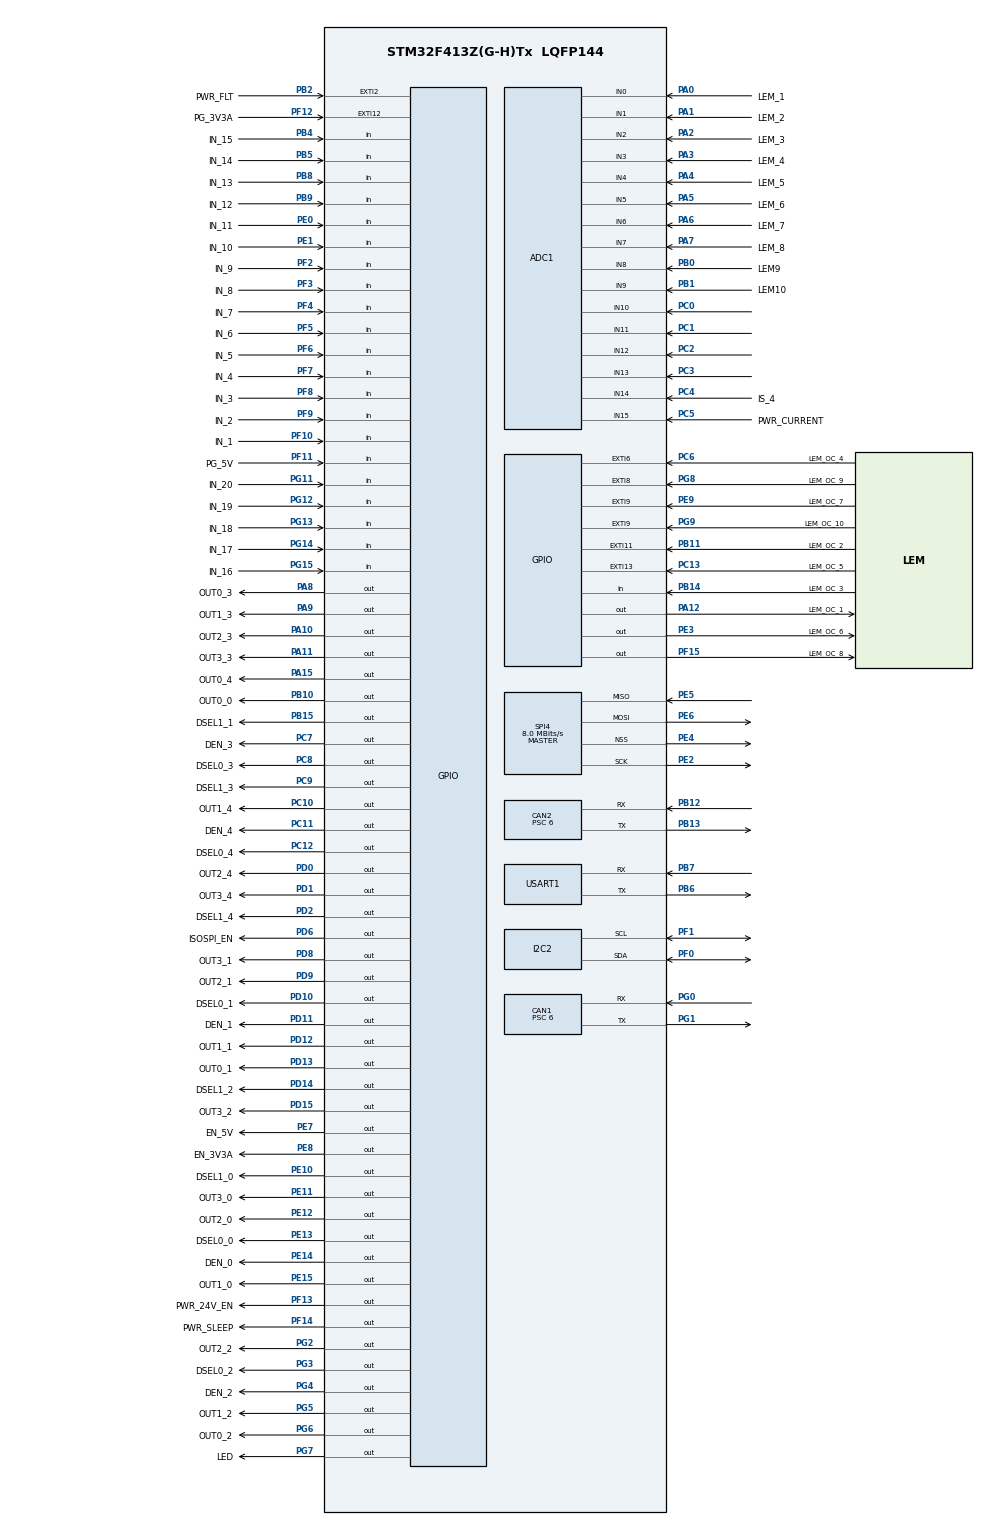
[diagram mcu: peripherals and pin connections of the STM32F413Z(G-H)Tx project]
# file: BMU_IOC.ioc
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ADC1.Channel-0\#ChannelRegularConversion=ADC_CHANNEL_0
ADC1.NbrOfConversionFlag=1
ADC1.Rank-0\#ChannelRegularConversion=1
ADC1.SamplingTime-0\#ChannelRegularConversion=ADC_SAMPLETIME_3CYCLES
ADC1.master=1
CAN1.BS1=CAN_BS1_13TQ
CAN1.BS2=CAN_BS2_2TQ
CAN1.CalculateBaudRate=500000
CAN1.CalculateTimeBit=2000
CAN1.CalculateTimeQuantum=125.0
CAN1.Prescaler=6
CAN2.BS1=CAN_BS1_13TQ
CAN2.BS2=CAN_BS2_2TQ
CAN2.CalculateBaudRate=500000
CAN2.CalculateTimeBit=2000
CAN2.CalculateTimeQuantum=125.0
CAN2.Prescaler=6
Mcu.Family=STM32F4
Mcu.Name=STM32F413Z(G-H)Tx
Mcu.Package=LQFP144
NVIC.PriorityGroup=NVIC_PRIORITYGROUP_4
PA0.GPIO_Label=LEM_1
PA0.Signal=ADCx_IN0
PA1.GPIO_Label=LEM_2
PA1.Signal=ADCx_IN1
PA10.GPIO_Label=OUT2_3
PA10.Signal=GPIO_Output
PA11.GPIO_Label=OUT3_3
PA11.Signal=GPIO_Output
PA12.GPIO_Label=LEM_OC_1
PA12.Signal=GPIO_Output
PA13.Mode=Trace_Asynchronous_SW
PA13.Signal=SYS_JTMS-SWDIO
PA14.Mode=Trace_Asynchronous_SW
PA14.Signal=SYS_JTCK-SWCLK
PA15.GPIO_Label=OUT0_4
PA15.Signal=GPIO_Output
PA2.GPIO_Label=LEM_3
PA2.Signal=ADCx_IN2
PA3.GPIO_Label=LEM_4
PA3.Signal=ADCx_IN3
PA4.GPIO_Label=LEM_5
PA4.Signal=ADCx_IN4
PA5.GPIO_Label=LEM_6
PA5.Signal=ADCx_IN5
PA6.GPIO_Label=LEM_7
PA6.Signal=ADCx_IN6
PA7.GPIO_Label=LEM_8
PA7.Signal=ADCx_IN7
PA8.GPIO_Label=OUT0_3
PA8.Signal=GPIO_Output
PA9.GPIO_Label=OUT1_3
PA9.Signal=GPIO_Output
PB0.GPIO_Label=LEM9
PB0.Signal=ADCx_IN8
PB1.GPIO_Label=LEM10
PB1.Signal=ADCx_IN9
PB10.GPIO_Label=OUT0_0
PB10.Signal=GPIO_Output
PB11.GPIO_Label=LEM_OC_2
PB11.Signal=GPXTI11
PB12.Mode=CAN_Activate
PB12.Signal=CAN2_RX
PB13.Mode=CAN_Activate
PB13.Signal=CAN2_TX
PB14.GPIO_Label=LEM_OC_3
PB14.Signal=GPIO_Input
PB15.GPIO_Label=DSEL1_1
PB15.Signal=GPIO_Output
PB2.GPIO_Label=PWR_FLT
PB2.Signal=GPXTI2
PB3.Mode=Trace_Asynchronous_SW
PB3.Signal=SYS_JTDO-SWO
PB4.GPIO_Label=IN_15
PB4.Signal=GPIO_Input
PB5.GPIO_Label=IN_14
PB5.Signal=GPIO_Input
PB6.Mode=Asynchronous
PB6.Signal=USART1_TX
PB7.Mode=Asynchronous
PB7.Signal=USART1_RX
PB8.GPIO_Label=IN_13
PB8.Signal=GPIO_Input
PB9.GPIO_Label=IN_12
PB9.Signal=GPIO_Input
PC0.Signal=ADCx_IN10
PC1.Signal=ADCx_IN11
PC10.GPIO_Label=OUT1_4
PC10.Signal=GPIO_Output
PC11.GPIO_Label=DEN_4
PC11.Signal=GPIO_Output
PC12.GPIO_Label=DSEL0_4
PC12.Signal=GPIO_Output
PC13.GPIO_Label=LEM_OC_5
PC13.Signal=GPXTI13
PC14-OSC32_IN.Mode=LSE-External-Oscillator
PC14-OSC32_IN.Signal=RCC_OSC32_IN
PC15-OSC32_OUT.Mode=LSE-External-Oscillator
PC15-OSC32_OUT.Signal=RCC_OSC32_OUT
PC2.Signal=ADCx_IN12
PC3.Signal=ADCx_IN13
PC4.GPIO_Label=IS_4
PC4.Signal=ADCx_IN14
PC5.GPIO_Label=PWR_CURRENT
PC5.Signal=ADCx_IN15
PC6.GPIO_Label=LEM_OC_4
PC6.Signal=GPXTI6
PC7.GPIO_Label=DEN_3
PC7.Signal=GPIO_Output
PC8.GPIO_Label=DSEL0_3
PC8.Signal=GPIO_Output
PC9.GPIO_Label=DSEL1_3
PC9.Signal=GPIO_Output
PD0.GPIO_Label=OUT2_4
PD0.Signal=GPIO_Output
PD1.GPIO_Label=OUT3_4
PD1.Signal=GPIO_Output
PD10.GPIO_Label=DSEL0_1
PD10.Signal=GPIO_Output
PD11.GPIO_Label=DEN_1
PD11.Signal=GPIO_Output
PD12.GPIO_Label=OUT1_1
PD12.Signal=GPIO_Output
PD13.GPIO_Label=OUT0_1
PD13.Signal=GPIO_Output
PD14.GPIO_Label=DSEL1_2
PD14.Signal=GPIO_Output
PD15.GPIO_Label=OUT3_2
PD15.Signal=GPIO_Output
PD2.GPIO_Label=DSEL1_4
PD2.Signal=GPIO_Output
PD6.GPIO_Label=ISOSPI_EN
PD6.Signal=GPIO_Output
PD8.GPIO_Label=OUT3_1
PD8.Signal=GPIO_Output
PD9.GPIO_Label=OUT2_1
PD9.Signal=GPIO_Output
PE0.GPIO_Label=IN_11
PE0.Signal=GPIO_Input
PE1.GPIO_Label=IN_10
PE1.Signal=GPIO_Input
PE10.GPIO_Label=DSEL1_0
PE10.Signal=GPIO_Output
PE11.GPIO_Label=OUT3_0
PE11.Signal=GPIO_Output
PE12.GPIO_Label=OUT2_0
PE12.Signal=GPIO_Output
PE13.GPIO_Label=DSEL0_0
PE13.Signal=GPIO_Output
PE14.GPIO_Label=DEN_0
PE14.Signal=GPIO_Output
PE15.GPIO_Label=OUT1_0
PE15.Signal=GPIO_Output
PE2.Mode=Full_Duplex_Master
PE2.Signal=SPI4_SCK
PE3.GPIO_Label=LEM_OC_6
PE3.Signal=GPIO_Output
PE4.Mode=NSS_Signal_Hard_Output
PE4.Signal=SPI4_NSS
PE5.Mode=Full_Duplex_Master
PE5.Signal=SPI4_MISO
PE6.Mode=Full_Duplex_Master
PE6.Signal=SPI4_MOSI
PE7.GPIO_Label=EN_5V
PE7.Signal=GPIO_Output
PE8.GPIO_Label=EN_3V3A
PE8.Signal=GPIO_Output
PE9.GPIO_Label=LEM_OC_7
PE9.Signal=GPXTI9
PF0.Mode=I2C
PF0.Signal=I2C2_SDA
PF1.Mode=I2C
PF1.Signal=I2C2_SCL
PF10.GPIO_Label=IN_1
PF10.Signal=GPIO_Input
PF11.GPIO_Label=PG_5V
PF11.Signal=GPIO_Input
PF12.GPIO_Label=PG_3V3A
PF12.Signal=GPXTI12
PF13.GPIO_Label=PWR_24V_EN
PF13.Signal=GPIO_Output
PF14.GPIO_Label=PWR_SLEEP
PF14.Signal=GPIO_Output
PF15.GPIO_Label=LEM_OC_8
PF15.Signal=GPIO_Output
PF2.GPIO_Label=IN_9
PF2.Signal=GPIO_Input
PF3.GPIO_Label=IN_8
PF3.Signal=GPIO_Input
PF4.GPIO_Label=IN_7
PF4.Signal=GPIO_Input
PF5.GPIO_Label=IN_6
PF5.Signal=GPIO_Input
PF6.GPIO_Label=IN_5
PF6.Signal=GPIO_Input
PF7.GPIO_Label=IN_4
PF7.Signal=GPIO_Input
PF8.GPIO_Label=IN_3
PF8.Signal=GPIO_Input
PF9.GPIO_Label=IN_2
PF9.Signal=GPIO_Input
PG0.Mode=CAN_Activate
PG0.Signal=CAN1_RX
PG1.Mode=CAN_Activate
PG1.Signal=CAN1_TX
PG11.GPIO_Label=IN_20
PG11.Signal=GPIO_Input
PG12.GPIO_Label=IN_19
PG12.Signal=GPIO_Input
PG13.GPIO_Label=IN_18
PG13.Signal=GPIO_Input
PG14.GPIO_Label=IN_17
PG14.Signal=GPIO_Input
PG15.GPIO_Label=IN_16
PG15.Signal=GPIO_Input
PG2.GPIO_Label=OUT2_2
PG2.Signal=GPIO_Output
PG3.GPIO_Label=DSEL0_2
PG3.Signal=GPIO_Output
PG4.GPIO_Label=DEN_2
PG4.Signal=GPIO_Output
PG5.GPIO_Label=OUT1_2
PG5.Signal=GPIO_Output
PG6.GPIO_Label=OUT0_2
PG6.Signal=GPIO_Output
PG7.GPIO_Label=LED
PG7.Signal=GPIO_Output
PG8.GPIO_Label=LEM_OC_9
PG8.Signal=GPXTI8
PG9.GPIO_Label=LEM_OC_10
PG9.Signal=GPXTI9
PH0\ -\ OSC_IN.Mode=HSE-External-Oscillator
PH0\ -\ OSC_IN.Signal=RCC_OSC_IN
PH1\ -\ OSC_OUT.Mode=HSE-External-Oscillator
PH1\ -\ OSC_OUT.Signal=RCC_OSC_OUT
ProjectManager.HeapSize=0x200
ProjectManager.StackSize=0x400
ProjectManager.TargetToolchain=STM32CubeIDE
RCC.CortexFreq_Value=16000000
RCC.USBFreq_Value=96000000
RCC.VCOOutputFreq_Value=192000000
SH.ADCx_IN0.0=ADC1_IN0,IN0
SH.ADCx_IN1.0=ADC1_IN1,IN1
SH.ADCx_IN10.0=ADC1_IN10,IN10
SH.ADCx_IN11.0=ADC1_IN11,IN11
SH.ADCx_IN12.0=ADC1_IN12,IN12
SH.ADCx_IN13.0=ADC1_IN13,IN13
SH.ADCx_IN14.0=ADC1_IN14,IN14
SH.ADCx_IN15.0=ADC1_IN15,IN15
SH.ADCx_IN2.0=ADC1_IN2,IN2
SH.ADCx_IN3.0=ADC1_IN3,IN3
SH.ADCx_IN4.0=ADC1_IN4,IN4
SH.ADCx_IN5.0=ADC1_IN5,IN5
SH.ADCx_IN6.0=ADC1_IN6,IN6
SH.ADCx_IN7.0=ADC1_IN7,IN7
SH.ADCx_IN8.0=ADC1_IN8,IN8
SH.ADCx_IN9.0=ADC1_IN9,IN9
SPI4.CalculateBaudRate=8.0 MBits/s
SPI4.Direction=SPI_DIRECTION_2LINES
SPI4.Mode=SPI_MODE_MASTER
SPI4.VirtualNSS=VM_NSSHARD
SPI4.VirtualType=VM_MASTER
USART1.VirtualMode=VM_ASYNC
board=custom

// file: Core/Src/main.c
/* USER CODE BEGIN Header */
/**
  ******************************************************************************
  * @file           : main.c
  * @brief          : Main program body
  ******************************************************************************
  * @attention
  *
  * Copyright (c) 2025 STMicroelectronics.
  * All rights reserved.
  *
  * This software is licensed under terms that can be found in the LICENSE file
  * in the root directory of this software component.
  * If no LICENSE file comes with this software, it is provided AS-IS.
  *
  ******************************************************************************
  */
/* USER CODE END Header */
#include "main.h"

/* USER CODE BEGIN Includes */
#include "bmu_test.h"
/* USER CODE END Includes */

ADC_HandleTypeDef hadc1;

CAN_HandleTypeDef hcan1;
CAN_HandleTypeDef hcan2;

I2C_HandleTypeDef hi2c2;

SPI_HandleTypeDef hspi4;

UART_HandleTypeDef huart1;

void SystemClock_Config(void);
static void MX_GPIO_Init(void);
static void MX_ADC1_Init(void);
static void MX_CAN1_Init(void);
static void MX_CAN2_Init(void);
static void MX_SPI4_Init(void);
static void MX_USART1_UART_Init(void);
static void MX_I2C2_Init(void);

/* USER CODE BEGIN 0 */

// UART receive buffer for commands
static uint8_t uart_rx_byte;
static volatile uint8_t uart_cmd_pending = 0;
static volatile char uart_cmd_char = 0;

/* USER CODE END 0 */

int main(void)
{

  /* MCU Configuration--------------------------------------------------------*/

  /* Reset of all peripherals, Initializes the Flash interface and the Systick. */
  HAL_Init();

  /* Configure the system clock */
  SystemClock_Config();

  /* Initialize all configured peripherals */
  MX_GPIO_Init();
  MX_ADC1_Init();
  MX_CAN1_Init();
  MX_CAN2_Init();
  MX_SPI4_Init();
  MX_USART1_UART_Init();
  MX_I2C2_Init();
  /* USER CODE BEGIN 2 */

  // Initialize BMU test suite
  BMU_Test_Init();

  // Start UART receive interrupt for command input
  HAL_UART_Receive_IT(&huart1, &uart_rx_byte, 1);

  /* USER CODE END 2 */

  /* Infinite loop */
  while (1)
  {

    /* USER CODE BEGIN 3 */

    // Process UART commands if pending
    if(uart_cmd_pending)
    {
      uart_cmd_pending = 0;  // Clear flag
      BMU_Test_ProcessCommand(uart_cmd_char);  // Process command
    }

    // Small delay to prevent busy loop
    HAL_Delay(10);

  }
  /* USER CODE END 3 */
}

void SystemClock_Config(void)
{
  RCC_OscInitTypeDef RCC_OscInitStruct = {0};
  RCC_ClkInitTypeDef RCC_ClkInitStruct = {0};

  /** Configure the main internal regulator output voltage
  */
  __HAL_RCC_PWR_CLK_ENABLE();
  __HAL_PWR_VOLTAGESCALING_CONFIG(PWR_REGULATOR_VOLTAGE_SCALE1);

  /** Initializes the RCC Oscillators according to the specified parameters
  * in the RCC_OscInitTypeDef structure.
  */
  RCC_OscInitStruct.OscillatorType = RCC_OSCILLATORTYPE_HSI;
  RCC_OscInitStruct.HSIState = RCC_HSI_ON;
  RCC_OscInitStruct.HSICalibrationValue = RCC_HSICALIBRATION_DEFAULT;
  RCC_OscInitStruct.PLL.PLLState = RCC_PLL_NONE;
  if (HAL_RCC_OscConfig(&RCC_OscInitStruct) != HAL_OK)
  {
    Error_Handler();
  }

  /** Initializes the CPU, AHB and APB buses clocks
  */
  RCC_ClkInitStruct.ClockType = RCC_CLOCKTYPE_HCLK|RCC_CLOCKTYPE_SYSCLK
                              |RCC_CLOCKTYPE_PCLK1|RCC_CLOCKTYPE_PCLK2;
  RCC_ClkInitStruct.SYSCLKSource = RCC_SYSCLKSOURCE_HSI;
  RCC_ClkInitStruct.AHBCLKDivider = RCC_SYSCLK_DIV1;
  RCC_ClkInitStruct.APB1CLKDivider = RCC_HCLK_DIV1;
  RCC_ClkInitStruct.APB2CLKDivider = RCC_HCLK_DIV1;

  if (HAL_RCC_ClockConfig(&RCC_ClkInitStruct, FLASH_LATENCY_0) != HAL_OK)
  {
    Error_Handler();
  }
}

static void MX_ADC1_Init(void)
{

  ADC_ChannelConfTypeDef sConfig = {0};

  /** Configure the global features of the ADC (Clock, Resolution, Data Alignment and number of conversion)
  */
  hadc1.Instance = ADC1;
  hadc1.Init.ClockPrescaler = ADC_CLOCK_SYNC_PCLK_DIV2;
  hadc1.Init.Resolution = ADC_RESOLUTION_12B;
  hadc1.Init.ScanConvMode = DISABLE;
  hadc1.Init.ContinuousConvMode = DISABLE;
  hadc1.Init.DiscontinuousConvMode = DISABLE;
  hadc1.Init.ExternalTrigConvEdge = ADC_EXTERNALTRIGCONVEDGE_NONE;
  hadc1.Init.ExternalTrigConv = ADC_SOFTWARE_START;
  hadc1.Init.DataAlign = ADC_DATAALIGN_RIGHT;
  hadc1.Init.NbrOfConversion = 1;
  hadc1.Init.DMAContinuousRequests = DISABLE;
  hadc1.Init.EOCSelection = ADC_EOC_SINGLE_CONV;
  if (HAL_ADC_Init(&hadc1) != HAL_OK)
  {
    Error_Handler();
  }

  /** Configure for the selected ADC regular channel its corresponding rank in the sequencer and its sample time.
  */
  sConfig.Channel = ADC_CHANNEL_0;
  sConfig.Rank = 1;
  sConfig.SamplingTime = ADC_SAMPLETIME_3CYCLES;
  if (HAL_ADC_ConfigChannel(&hadc1, &sConfig) != HAL_OK)
  {
    Error_Handler();
  }

}

static void MX_CAN1_Init(void)
{

  hcan1.Instance = CAN1;
  hcan1.Init.Prescaler = 16;
  hcan1.Init.Mode = CAN_MODE_NORMAL;
  hcan1.Init.SyncJumpWidth = CAN_SJW_1TQ;
  hcan1.Init.TimeSeg1 = CAN_BS1_1TQ;
  hcan1.Init.TimeSeg2 = CAN_BS2_1TQ;
  hcan1.Init.TimeTriggeredMode = DISABLE;
  hcan1.Init.AutoBusOff = DISABLE;
  hcan1.Init.AutoWakeUp = DISABLE;
  hcan1.Init.AutoRetransmission = DISABLE;
  hcan1.Init.ReceiveFifoLocked = DISABLE;
  hcan1.Init.TransmitFifoPriority = DISABLE;
  if (HAL_CAN_Init(&hcan1) != HAL_OK)
  {
    Error_Handler();
  }

}

static void MX_CAN2_Init(void)
{

  hcan2.Instance = CAN2;
  hcan2.Init.Prescaler = 16;
  hcan2.Init.Mode = CAN_MODE_NORMAL;
  hcan2.Init.SyncJumpWidth = CAN_SJW_1TQ;
  hcan2.Init.TimeSeg1 = CAN_BS1_1TQ;
  hcan2.Init.TimeSeg2 = CAN_BS2_1TQ;
  hcan2.Init.TimeTriggeredMode = DISABLE;
  hcan2.Init.AutoBusOff = DISABLE;
  hcan2.Init.AutoWakeUp = DISABLE;
  hcan2.Init.AutoRetransmission = DISABLE;
  hcan2.Init.ReceiveFifoLocked = DISABLE;
  hcan2.Init.TransmitFifoPriority = DISABLE;
  if (HAL_CAN_Init(&hcan2) != HAL_OK)
  {
    Error_Handler();
  }

}

static void MX_I2C2_Init(void)
{

  hi2c2.Instance = I2C2;
  hi2c2.Init.ClockSpeed = 100000;
  hi2c2.Init.DutyCycle = I2C_DUTYCYCLE_2;
  hi2c2.Init.OwnAddress1 = 0;
  hi2c2.Init.AddressingMode = I2C_ADDRESSINGMODE_7BIT;
  hi2c2.Init.DualAddressMode = I2C_DUALADDRESS_DISABLE;
  hi2c2.Init.OwnAddress2 = 0;
  hi2c2.Init.GeneralCallMode = I2C_GENERALCALL_DISABLE;
  hi2c2.Init.NoStretchMode = I2C_NOSTRETCH_DISABLE;
  if (HAL_I2C_Init(&hi2c2) != HAL_OK)
  {
    Error_Handler();
  }

}

static void MX_SPI4_Init(void)
{

  /* SPI4 parameter configuration*/
  hspi4.Instance = SPI4;
  hspi4.Init.Mode = SPI_MODE_MASTER;
  hspi4.Init.Direction = SPI_DIRECTION_2LINES;
  hspi4.Init.DataSize = SPI_DATASIZE_8BIT;
  hspi4.Init.CLKPolarity = SPI_POLARITY_LOW;
  hspi4.Init.CLKPhase = SPI_PHASE_1EDGE;
  hspi4.Init.NSS = SPI_NSS_HARD_OUTPUT;
  hspi4.Init.BaudRatePrescaler = SPI_BAUDRATEPRESCALER_2;
  hspi4.Init.FirstBit = SPI_FIRSTBIT_MSB;
  hspi4.Init.TIMode = SPI_TIMODE_DISABLE;
  hspi4.Init.CRCCalculation = SPI_CRCCALCULATION_DISABLE;
  hspi4.Init.CRCPolynomial = 10;
  if (HAL_SPI_Init(&hspi4) != HAL_OK)
  {
    Error_Handler();
  }

}

static void MX_USART1_UART_Init(void)
{

  huart1.Instance = USART1;
  huart1.Init.BaudRate = 115200;
  huart1.Init.WordLength = UART_WORDLENGTH_8B;
  huart1.Init.StopBits = UART_STOPBITS_1;
  huart1.Init.Parity = UART_PARITY_NONE;
  huart1.Init.Mode = UART_MODE_TX_RX;
  huart1.Init.HwFlowCtl = UART_HWCONTROL_NONE;
  huart1.Init.OverSampling = UART_OVERSAMPLING_16;
  if (HAL_UART_Init(&huart1) != HAL_OK)
  {
    Error_Handler();
  }

}

static void MX_GPIO_Init(void)
{
  GPIO_InitTypeDef GPIO_InitStruct = {0};

  /* GPIO Ports Clock Enable */
  __HAL_RCC_GPIOE_CLK_ENABLE();
  __HAL_RCC_GPIOC_CLK_ENABLE();
  __HAL_RCC_GPIOF_CLK_ENABLE();
  __HAL_RCC_GPIOH_CLK_ENABLE();
  __HAL_RCC_GPIOA_CLK_ENABLE();
  __HAL_RCC_GPIOB_CLK_ENABLE();
  __HAL_RCC_GPIOG_CLK_ENABLE();
  __HAL_RCC_GPIOD_CLK_ENABLE();

  /*Configure GPIO pin Output Level */
  HAL_GPIO_WritePin(GPIOE, ISOSPI_EN_Pin|EN_5V_Pin|EN_3V3A_Pin|DEN_0_Pin
                          |DSEL0_0_Pin|DSEL1_0_Pin|OUT0_0_Pin|OUT1_0_Pin
                          |OUT2_0_Pin, GPIO_PIN_RESET);

  /*Configure GPIO pin Output Level */
  HAL_GPIO_WritePin(GPIOF, PWR_EN_Pin|PWR_SLEEP_Pin|CAN_RS_Pin, GPIO_PIN_RESET);

  /*Configure GPIO pin Output Level */
  HAL_GPIO_WritePin(GPIOB, OUT3_0_Pin|CAN2_RS_Pin|DEN_1_Pin, GPIO_PIN_RESET);

  /*Configure GPIO pin Output Level */
  HAL_GPIO_WritePin(GPIOD, DSEL0_1_Pin|DSEL1_1_Pin|OUT0_1_Pin|OUT1_1_Pin
                          |OUT2_1_Pin|OUT3_1_Pin|DEN_2_Pin|DSEL0_2_Pin
                          |OUT1_4_Pin|OUT2_4_Pin|OUT3_4_Pin|DEN_5_Pin
                          |DSEL0_5_Pin|DSEL1_5_Pin|OUT0_5_Pin|OUT1_5_Pin, GPIO_PIN_RESET);

  /*Configure GPIO pin Output Level */
  HAL_GPIO_WritePin(GPIOG, DSEL1_2_Pin|OUT0_2_Pin|OUT1_2_Pin|OUT2_2_Pin
                          |OUT3_2_Pin|LED_Pin|OUT2_5_Pin|OUT3_5_Pin, GPIO_PIN_RESET);

  /*Configure GPIO pin Output Level */
  HAL_GPIO_WritePin(GPIOC, DEN_3_Pin|DSEL0_3_Pin|DSEL1_3_Pin|DSEL0_4_Pin
                          |DSEL1_4_Pin|OUT0_4_Pin, GPIO_PIN_RESET);

  /*Configure GPIO pin Output Level */
  HAL_GPIO_WritePin(GPIOA, OUT0_3_Pin|OUT1_3_Pin|OUT2_3_Pin|OUT3_3_Pin
                          |WP_FRAM_Pin|DEN_4_Pin, GPIO_PIN_RESET);

  /*Configure GPIO pins : ISOSPI_EN_Pin EN_5V_Pin EN_3V3A_Pin DEN_0_Pin
                           DSEL0_0_Pin DSEL1_0_Pin OUT0_0_Pin OUT1_0_Pin
                           OUT2_0_Pin */
  GPIO_InitStruct.Pin = ISOSPI_EN_Pin|EN_5V_Pin|EN_3V3A_Pin|DEN_0_Pin
                          |DSEL0_0_Pin|DSEL1_0_Pin|OUT0_0_Pin|OUT1_0_Pin
                          |OUT2_0_Pin;
  GPIO_InitStruct.Mode = GPIO_MODE_OUTPUT_PP;
  GPIO_InitStruct.Pull = GPIO_NOPULL;
  GPIO_InitStruct.Speed = GPIO_SPEED_FREQ_LOW;
  HAL_GPIO_Init(GPIOE, &GPIO_InitStruct);

  /*Configure GPIO pins : TMP_ALRT_Pin OC_4_Pin */
  GPIO_InitStruct.Pin = TMP_ALRT_Pin|OC_4_Pin;
  GPIO_InitStruct.Mode = GPIO_MODE_IT_RISING;
  GPIO_InitStruct.Pull = GPIO_NOPULL;
  HAL_GPIO_Init(GPIOC, &GPIO_InitStruct);

  /*Configure GPIO pins : IN_8_Pin IN_7_Pin IN_6_Pin IN_5_Pin
                           IN_4_Pin IN_3_Pin IN_2_Pin IN_1_Pin
                           IN_0_Pin PG_5V_Pin */
  GPIO_InitStruct.Pin = IN_8_Pin|IN_7_Pin|IN_6_Pin|IN_5_Pin
                          |IN_4_Pin|IN_3_Pin|IN_2_Pin|IN_1_Pin
                          |IN_0_Pin|PG_5V_Pin;
  GPIO_InitStruct.Mode = GPIO_MODE_INPUT;
  GPIO_InitStruct.Pull = GPIO_NOPULL;
  HAL_GPIO_Init(GPIOF, &GPIO_InitStruct);

  /*Configure GPIO pins : PWR_FLT_Pin OC_2_Pin */
  GPIO_InitStruct.Pin = PWR_FLT_Pin|OC_2_Pin;
  GPIO_InitStruct.Mode = GPIO_MODE_IT_RISING;
  GPIO_InitStruct.Pull = GPIO_NOPULL;
  HAL_GPIO_Init(GPIOB, &GPIO_InitStruct);

  /*Configure GPIO pin : PG_3V3A_Pin */
  GPIO_InitStruct.Pin = PG_3V3A_Pin;
  GPIO_InitStruct.Mode = GPIO_MODE_IT_RISING;
  GPIO_InitStruct.Pull = GPIO_NOPULL;
  HAL_GPIO_Init(PG_3V3A_GPIO_Port, &GPIO_InitStruct);

  /*Configure GPIO pins : PWR_EN_Pin PWR_SLEEP_Pin CAN_RS_Pin */
  GPIO_InitStruct.Pin = PWR_EN_Pin|PWR_SLEEP_Pin|CAN_RS_Pin;
  GPIO_InitStruct.Mode = GPIO_MODE_OUTPUT_PP;
  GPIO_InitStruct.Pull = GPIO_NOPULL;
  GPIO_InitStruct.Speed = GPIO_SPEED_FREQ_LOW;
  HAL_GPIO_Init(GPIOF, &GPIO_InitStruct);

  /*Configure GPIO pin : OC_7_Pin */
  GPIO_InitStruct.Pin = OC_7_Pin;
  GPIO_InitStruct.Mode = GPIO_MODE_IT_RISING;
  GPIO_InitStruct.Pull = GPIO_NOPULL;
  HAL_GPIO_Init(OC_7_GPIO_Port, &GPIO_InitStruct);

  /*Configure GPIO pins : OUT3_0_Pin CAN2_RS_Pin DEN_1_Pin */
  GPIO_InitStruct.Pin = OUT3_0_Pin|CAN2_RS_Pin|DEN_1_Pin;
  GPIO_InitStruct.Mode = GPIO_MODE_OUTPUT_PP;
  GPIO_InitStruct.Pull = GPIO_NOPULL;
  GPIO_InitStruct.Speed = GPIO_SPEED_FREQ_LOW;
  HAL_GPIO_Init(GPIOB, &GPIO_InitStruct);

  /*Configure GPIO pins : DSEL0_1_Pin DSEL1_1_Pin OUT0_1_Pin OUT1_1_Pin
                           OUT2_1_Pin OUT3_1_Pin DEN_2_Pin DSEL0_2_Pin
                           OUT1_4_Pin OUT2_4_Pin OUT3_4_Pin DEN_5_Pin
                           DSEL0_5_Pin DSEL1_5_Pin OUT0_5_Pin OUT1_5_Pin */
  GPIO_InitStruct.Pin = DSEL0_1_Pin|DSEL1_1_Pin|OUT0_1_Pin|OUT1_1_Pin
                          |OUT2_1_Pin|OUT3_1_Pin|DEN_2_Pin|DSEL0_2_Pin
                          |OUT1_4_Pin|OUT2_4_Pin|OUT3_4_Pin|DEN_5_Pin
                          |DSEL0_5_Pin|DSEL1_5_Pin|OUT0_5_Pin|OUT1_5_Pin;
  GPIO_InitStruct.Mode = GPIO_MODE_OUTPUT_PP;
  GPIO_InitStruct.Pull = GPIO_NOPULL;
  GPIO_InitStruct.Speed = GPIO_SPEED_FREQ_LOW;
  HAL_GPIO_Init(GPIOD, &GPIO_InitStruct);

  /*Configure GPIO pins : DSEL1_2_Pin OUT0_2_Pin OUT1_2_Pin OUT2_2_Pin
                           OUT3_2_Pin LED_Pin OUT2_5_Pin OUT3_5_Pin */
  GPIO_InitStruct.Pin = DSEL1_2_Pin|OUT0_2_Pin|OUT1_2_Pin|OUT2_2_Pin
                          |OUT3_2_Pin|LED_Pin|OUT2_5_Pin|OUT3_5_Pin;
  GPIO_InitStruct.Mode = GPIO_MODE_OUTPUT_PP;
  GPIO_InitStruct.Pull = GPIO_NOPULL;
  GPIO_InitStruct.Speed = GPIO_SPEED_FREQ_LOW;
  HAL_GPIO_Init(GPIOG, &GPIO_InitStruct);

  /*Configure GPIO pin : OC_9_Pin */
  GPIO_InitStruct.Pin = OC_9_Pin;
  GPIO_InitStruct.Mode = GPIO_MODE_IT_RISING;
  GPIO_InitStruct.Pull = GPIO_NOPULL;
  HAL_GPIO_Init(OC_9_GPIO_Port, &GPIO_InitStruct);

  /*Configure GPIO pins : DEN_3_Pin DSEL0_3_Pin DSEL1_3_Pin DSEL0_4_Pin
                           DSEL1_4_Pin OUT0_4_Pin */
  GPIO_InitStruct.Pin = DEN_3_Pin|DSEL0_3_Pin|DSEL1_3_Pin|DSEL0_4_Pin
                          |DSEL1_4_Pin|OUT0_4_Pin;
  GPIO_InitStruct.Mode = GPIO_MODE_OUTPUT_PP;
  GPIO_InitStruct.Pull = GPIO_NOPULL;
  GPIO_InitStruct.Speed = GPIO_SPEED_FREQ_LOW;
  HAL_GPIO_Init(GPIOC, &GPIO_InitStruct);

  /*Configure GPIO pins : OUT0_3_Pin OUT1_3_Pin OUT2_3_Pin OUT3_3_Pin
                           WP_FRAM_Pin DEN_4_Pin */
  GPIO_InitStruct.Pin = OUT0_3_Pin|OUT1_3_Pin|OUT2_3_Pin|OUT3_3_Pin
                          |WP_FRAM_Pin|DEN_4_Pin;
  GPIO_InitStruct.Mode = GPIO_MODE_OUTPUT_PP;
  GPIO_InitStruct.Pull = GPIO_NOPULL;
  GPIO_InitStruct.Speed = GPIO_SPEED_FREQ_LOW;
  HAL_GPIO_Init(GPIOA, &GPIO_InitStruct);

  /*Configure GPIO pins : IN_19_Pin IN_18_Pin IN_17_Pin IN_16_Pin
                           IN_15_Pin */
  GPIO_InitStruct.Pin = IN_19_Pin|IN_18_Pin|IN_17_Pin|IN_16_Pin
                          |IN_15_Pin;
  GPIO_InitStruct.Mode = GPIO_MODE_INPUT;
  GPIO_InitStruct.Pull = GPIO_NOPULL;
  HAL_GPIO_Init(GPIOG, &GPIO_InitStruct);

  /*Configure GPIO pins : IN_14_Pin IN_13_Pin IN_12_Pin IN_11_Pin */
  GPIO_InitStruct.Pin = IN_14_Pin|IN_13_Pin|IN_12_Pin|IN_11_Pin;
  GPIO_InitStruct.Mode = GPIO_MODE_INPUT;
  GPIO_InitStruct.Pull = GPIO_NOPULL;
  HAL_GPIO_Init(GPIOB, &GPIO_InitStruct);

  /*Configure GPIO pins : IN_10_Pin IN_9_Pin */
  GPIO_InitStruct.Pin = IN_10_Pin|IN_9_Pin;
  GPIO_InitStruct.Mode = GPIO_MODE_INPUT;
  GPIO_InitStruct.Pull = GPIO_NOPULL;
  HAL_GPIO_Init(GPIOE, &GPIO_InitStruct);

}

/* USER CODE BEGIN 4 */

/**
  * @brief  UART Receive Complete Callback
  * @param  huart: UART handle
  * @retval None
  */
void HAL_UART_RxCpltCallback(UART_HandleTypeDef *huart)
{
  if(huart->Instance == USART1)
  {
    // Set flag and save character for processing in main loop
    uart_cmd_char = (char)uart_rx_byte;
    uart_cmd_pending = 1;

    // Restart UART receive interrupt
    HAL_UART_Receive_IT(&huart1, &uart_rx_byte, 1);
  }
}

/* USER CODE END 4 */

void Error_Handler(void)
{
  __disable_irq();
  while (1)
  {
  }
}
